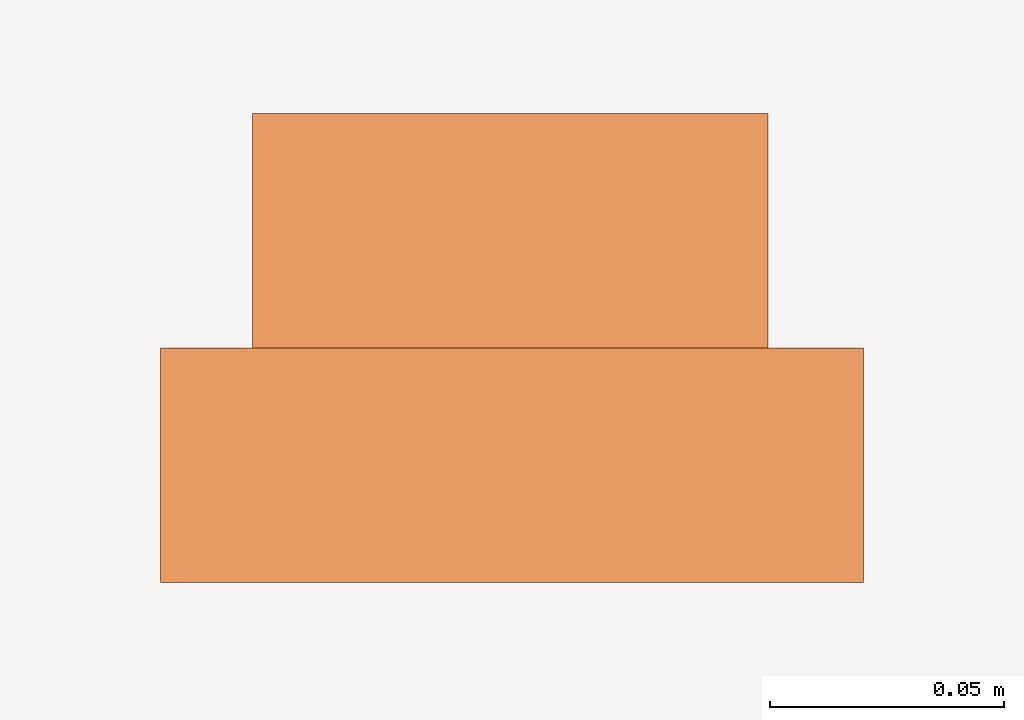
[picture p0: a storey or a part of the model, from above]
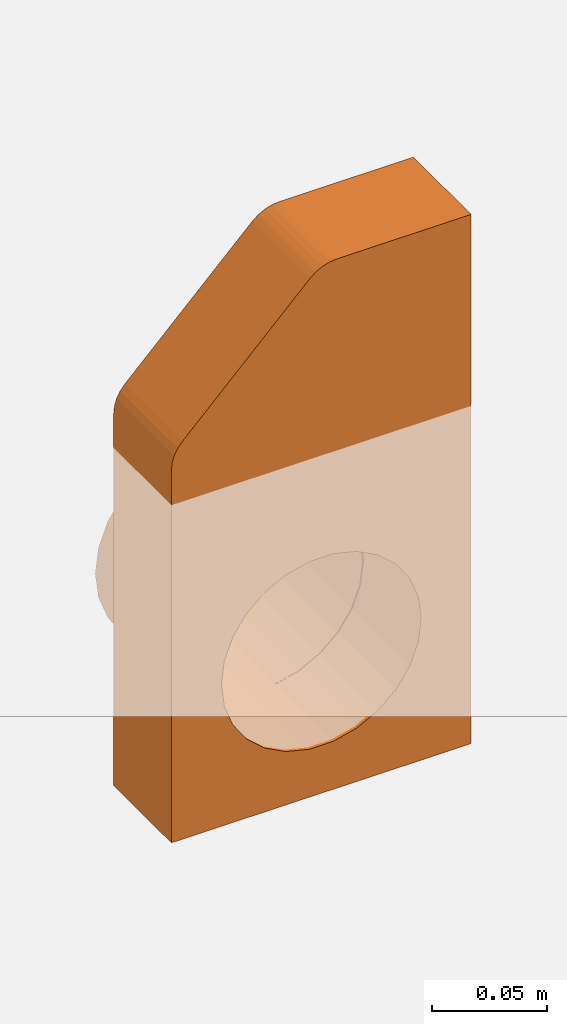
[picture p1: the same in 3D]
Properties of the parts of a building model (IFC2X3)

# File
Description: ViewDefinition [CoordinationView]
File name: 7943 - RH inlet-outlet end cap.ifc
Time: 2013-09-02T12:35:14
Written by: Autodesk Revit 2013
Made in: 20120221_2030(x64)

# IfcProject, Project Number
LongName: Project Name; Phase: Project Status

# IfcSite, Default
RefLatitude: 42, 21, 30, 344238; RefLongitude: -71, -3, -35, -194702; RefElevation: 0 mm

# IfcBuilding
Pset_BuildingCommon - NumberOfStoreys: 1
Other - Project Status: Project Status; Project Number: Project Number; Project Issue Date: Issue Date; Client Name: Owner; Project Address: ## Street City, State Zip; Project Name: Project Name

# IfcBuildingStorey, Level 1
LongName: Level 1; Elevation: 0 mm
Graphics - Symbol: M_Level Head - Circle: M_Level Head - Circle; Symbol at End 1 Default: no; Line Weight: 1; Symbol at End 2 Default: yes; Line Pattern: Center; Color: 0
Constraints - Elevation Base: 0; Elevation: 0 mm
Dimensions - Computation Height: 0 mm
Identity Data - Structural: no; Name: Level 1; Building Story: yes

# IfcBuildingElementProxy: 7943 - RH inlet/outlet end cap, Civil-Drainage-Channel-ACO-KerbDrain-SP280:7943 - RH inlet/outlet end cap:7943 - RH inlet/outlet end cap:311063
In: Level 1
Material: Orange, ACO Polymer Concrete.
Green Building Properties - Channel Recyclable: N/A; End Cap Recyclable: Fully recyclable; Channel Recycled Material Content: N/A; End Cap Recycled Material Content: 20% minimum; Access Cover/Frame Recycled Material Content: N/A; Access Cover/Frame Recyclable: N/A
Phasing - Phase Created: New Construction
Constraints - Moves With Nearby Elements: no; Level: Level: Level 1
Dimensions - Volume: 1648380 mm3; Void Width: 150 mm; Access hole: 2 mm; Endcap void: 230 mm; Void Length: 50 mm; Void Depth: -180 mm; AccessDepth: 2000 mm
Pset_BuildingElementProxyCommon - Reference: 7943 - RH inlet/outlet end cap
Data - Product Dimensions: 50mm x 150mm x 280mm (LxWxH); Concrete Surround Volume - Load Class A 15 - D 400 - Grass or Asphalt Pavement: N/A; Concrete Surround Volume - Load Class A 15 - D 400 - Concrete Pavement: N/A; Drainage Slot Width: N/A; Product Weight: 3.4 Kg; Installation - Concrete Grade: N/A; Load Class: N/A; Drainage Slot Intake area: N/A; Product Standard: N/A; Channel C.S.A: N/A; Invert Depth: N/A; Connection Pipe O.D: Ø110mm; ACO Hydraulic Design Software: N/A; Hydraulic Performance: N/A
Materials and Finishes - Access Cover/Frame Material: N/A; Access Cover/Frame Finish: N/A; Connection Pipe Material: PVCu; End Cap Material: Vienite® Synthetic Resin Concrete; Connection Pipe Material Colour: Brown; Channel Colour: N/A; Access Cover/Frame Colour: N/A; End Cap Colour: Grey; Channel Material: N/A
Other - Revision: 1; CreatedBy: www.aco.co.uk
Identity Data - Cost: 0; Assembly Description: Rain Water Drainage; OmniClass Number: 23.70.50.24; Maintenance guidelines: http://www.aco.co.uk/download.php?id=120; Price: POA - contact ACO; e-mail Sales: customersupport@aco.co.uk; Type Comments: ACO KerbDrain SP280 splayed RH inlet / outlet end cap; Installation guidelines: http://www.aco.co.uk/download.php?id=120; OmniClass Title: Rainwater Removal; Model Description: Combined kerb and drainage system; Model: ACO KerbDrain SP280; Product Page URL: http://www.aco.co.uk/product_detail.php?id=3; Manufacturer: ACO Technologies plc - ACO Water Management Division; Product Code: 7943; URL: www.aco.co.uk; Fax: +44 (0)1462 815895; Product brochure: http://www.aco.co.uk/download.php?id=120; Assembly Code: D2040; Address: ACO Business Park, Hitchin Road, Shefford, Bedfordshire, United Kingdom SG17 5TE; Telephone: +44 (0)1462 816666; e-mail Technical: technical@aco.co.uk
General - SerialNumber: 0.000000; TagNumber: 0.000000
Construction - RH inlet/outlet end cap: yes; perforated centre stone: no; RH transition unit: no; LH transition unit: no; Centre Stone: no; LH drop kerb: no; Access Unit: no; SP280 - 1000: no; SP280-500: no; Closing end cap: no; RH drop kerb: no; LH inlet/outlet end cap: no

# IfcOpeningElement: Recess (2)
In: Level 1
Constraints - Level: Level: Level 1; Related to Mass: no; Height Offset From Level: 0 mm; Room Bounding: yes
Structural - Structural: no; Enable Analytical Model: no
Dimensions - Thickness: 400 mm; Perimeter: 51360 mm; Volume: 60586181707 mm3; Area: 151470000 mm2
Phasing - Phase Created: New Construction
Construction - Default Thickness: 400 mm; Function: 0
Analytical Properties - Roughness: 1; Absorptance: 0.1
Materials and Finishes - Structural Material: Plant
Graphics - Coarse Scale Fill Color: 0

# IfcSlab: Floor:Generic Floor - 400mm, Floor:Generic Floor - 400mm:193825
In: Level 1
PredefinedType: FLOOR; Material: Plant 400 mm
Constraints - Level: Level: Level 1; Related to Mass: no; Height Offset From Level: 0 mm; Room Bounding: yes
Structural - Structural: no; Enable Analytical Model: no
Dimensions - Thickness: 400 mm; Perimeter: 51360 mm; Volume: 60586181707 mm3; Area: 151470000 mm2
Phasing - Phase Created: New Construction
Pset_SlabCommon - Reference: Generic Floor - 400mm; IsExternal: no; LoadBearing: yes
Construction - Default Thickness: 400 mm; Function: 0
Analytical Properties - Roughness: 1; Absorptance: 0.1
Materials and Finishes - Structural Material: Plant
Graphics - Coarse Scale Fill Color: 0
